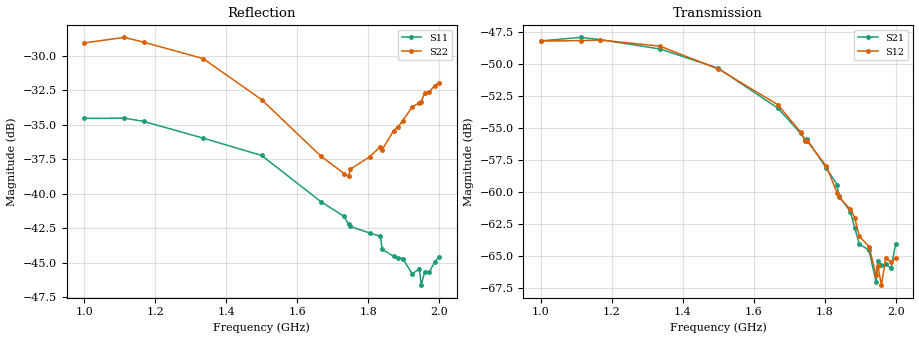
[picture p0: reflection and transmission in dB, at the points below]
!Agilent Technologies,E8363C,MY43030407,A.09.42.15
!Agilent E8363C: A.09.42.15
!Date: Friday, September 05, 2025 18:12:03
!Correction: S11(Full 2 Port(1,2))
!S21(Full 2 Port(1,2))
!S12(Full 2 Port(1,2))
!S22(Full 2 Port(1,2))
!S2P File: Measurements: S11, S21, S12, S22:
# Hz S  dB  R 50
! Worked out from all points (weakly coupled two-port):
!   401 points, 1 GHz to 2 GHz, reference 50 ohm
!   highest |S21| = -47.90 dB at 1.113 GHz (marker M1); lowest = -67.0 dB at 1.945 GHz (marker M2)
!   lowest |S11| = -46.6 dB at 1.95 GHz (marker M3), VSWR 1.01, Z = 49.5 + j0.0664 ohm
!   |S11| at or under -10 dB: start of sweep to end of sweep
!   |S22| runs from -38.7 to -28.7 dB; largest |S21 - S12| = 0.00016
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1e9  -34.54 179.5  -48.17 -59.5  -48.19 -60.1  -29.06 -155.4
1.1125e9  -34.52 168.8  -47.90 -80.9  -48.15 -81.5  -28.66 -169.8
1.1675e9  -34.76 166.1  -48.08 -91.2  -48.11 -91.2  -29.01 -176.7
1.335e9  -35.97 150.5  -48.80 -122.8  -48.58 -123.2  -30.20 157.6
1.5e9  -37.23 138.7  -50.31 -154.8  -50.37 -154.1  -33.18 129.7
1.6675e9  -40.59 141.8  -53.42 170.7  -53.15 169.9  -37.29 78.6
1.7325e9  -41.65 141.2  -55.40 155.6  -55.31 157.0  -38.54 48.9
1.745e9  -42.23 144.1  -55.88 152.9  -55.98 150.4  -38.75 40.2
1.75e9  -42.38 142.5  -55.86 152.1  -55.97 148.5  -38.23 36.9
1.805e9  -42.86 142.5  -58.13 135.4  -57.97 135.8  -37.32 10.0
1.835e9  -43.10 144.2  -59.40 126.6  -60.06 125.3  -36.58 -0.9
1.84e9  -44.05 149.2  -60.27 121.7  -60.37 123.4  -36.80 -0.8
1.8725e9  -44.55 160.7  -61.51 109.7  -61.33 104.5  -35.42 -13.7
1.885e9  -44.66 162.5  -62.80 99.0  -62.01 100.5  -35.15 -19.6
1.8975e9  -44.71 158.0  -64.03 94.0  -63.43 94.8  -34.72 -20.1
1.925e9  -45.83 164.8  -64.53 74.6  -64.24 71.1  -33.70 -29.9
1.945e9  -45.44 171.9  -67.02 59.2  -66.48 62.8  -33.40 -34.8
1.95e9  -46.64 171.7  -65.39 50.8  -65.72 47.3  -33.32 -35.2
1.96e9  -45.66 175.4  -65.67 39.1  -67.25 47.5  -32.68 -36.8
1.9725e9  -45.71 169.3  -65.63 35.6  -65.10 27.3  -32.64 -39.5
1.9875e9  -44.99 173.2  -65.93 17.4  -65.48 23.4  -32.16 -42.3
2e9  -44.59 174.7  -64.03 8.3  -65.13 11.1  -31.96 -47.0
